! (c) 2009  Infineon Technologies AG, Munich
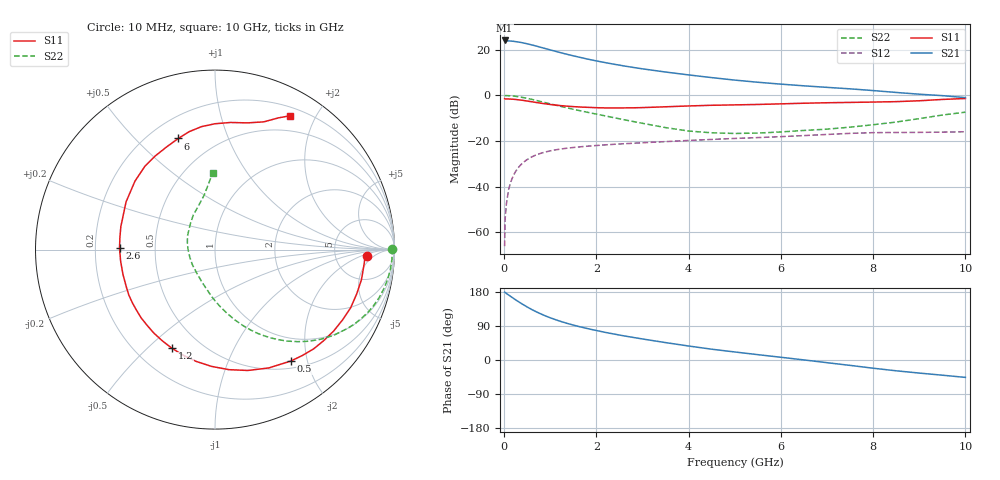
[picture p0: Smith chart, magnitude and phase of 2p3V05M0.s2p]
! Infineon Technologies  Discrete & RF Semiconductors
! BFP420
! VCE =  3.0 V,  IC =  5.0 mA
! Common Emitter S-Parameters:  Nov 2009
# GHz  S  MA  R  50
!  f  S11  S21  S12  S22
! GHz  MAG  ANG  MAG  ANG  MAG  ANG  MAG  ANG
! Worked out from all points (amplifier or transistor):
!   46 points, 10 MHz to 10 GHz, reference 50 ohm
!   highest |S21| = 24.0 dB at 10 MHz (marker M1)
!   |S21| within 3 dB of that: start of sweep to 793.4 MHz
!   unconditionally stable (mu >= 1): start of sweep to 10.09 MHz; 3.014 GHz to end of sweep
!   at 300 MHz: K = 0.11, MSG = 27.6 dB, |S12| = -31.8 dB
!   at 1.7 GHz: K = 0.59, MSG = 19.4 dB, |S12| = -22.4 dB
!   at 10 GHz: K = 1.13, MAG = 5.3 dB, |S12| = -15.9 dB
!   lowest NFmin = 0.66 dB at 900 MHz
!   S11 on the Smith chart (normalised r, x): 10 MHz: 11, -3; 500 MHz: 0.61, -1.73; 1.2 GHz: 0.35, -0.60; 2.6 GHz: 0.31, +0.01; 6 GHz: 0.31, +0.67; 10 GHz: 0.30, +1.66
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0.01  0.8454 -2.4  15.92 179.1  0.0005 50.0  0.986 0.3
0.02  0.8378 -2.3  15.55 178.3  0.0019 81.9  0.9876 -1.3
0.1  0.8331 -11.6  15.57 171.3  0.009 82.6  0.9834 -6.6
0.2  0.8224 -23.2  15.26 162.9  0.0176 77.4  0.9655 -13.1
0.3  0.8019 -34.4  14.77 154.7  0.0256 72.2  0.9375 -19.4
0.4  0.7796 -45.2  14.15 147.1  0.0329 66.9  0.9009 -25.2
0.5  0.7512 -55.7  13.45 139.9  0.0394 62.3  0.8602 -30.6
0.6  0.7241 -65.6  12.72 133.1  0.0451 57.8  0.8171 -35.7
0.8  0.6734 -83.4  11.22 121.4  0.0542 50.6  0.731 -44.3
1  0.6318 -99.5  9.896 111.4  0.061 45.0  0.6516 -51.5
1.2  0.5998 -113.6  8.732 102.8  0.0662 40.6  0.5823 -57.7
1.4  0.5768 -126.1  7.758 95.4  0.0704 37.1  0.523 -63.1
1.7  0.5526 -142.4  6.595 86.0  0.0756 33.1  0.4486 -70.0
2.2  0.5311 -165.0  5.194 72.7  0.0826 28.2  0.3538 -80.2
2.6  0.532 179.2  4.407 63.6  0.0873 25.2  0.2931 -88.7
3.5  0.5623 151.8  3.241 45.9  0.0972 20.0  0.1969 -111.2
4.5  0.6069 130.0  2.447 28.5  0.1085 14.5  0.1515 -146.2
5.5  0.6324 115.2  1.937 14.1  0.1191 9.5  0.1496 -178.5
6  0.6522 108.3  1.762 7.2  0.1249 7.1  0.1583 166.7
7  0.6894 96.2  1.497 -7.1  0.1395 1.0  0.1821 142.9
8.5  0.7289 75.6  1.158 -28.5  0.154 -12.6  0.2605 110.7
10  0.854 60.8  0.893 -45.9  0.1596 -21.5  0.4286 91.7
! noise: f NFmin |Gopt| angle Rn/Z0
0.9  0.66  0.21  31  0.15
1.8  1.05  0.09  93  0.13
2.4  1.14  0.14  119  0.13
3  1.24  0.17  165  0.11
4  1.41  0.31  -145  0.12
5  1.85  0.38  -119  0.21
6  2.3  0.45  -101  0.36
